VERSION 5.8 ;
BUSBITCHARS "[]" ;
DIVIDERCHAR "/" ;

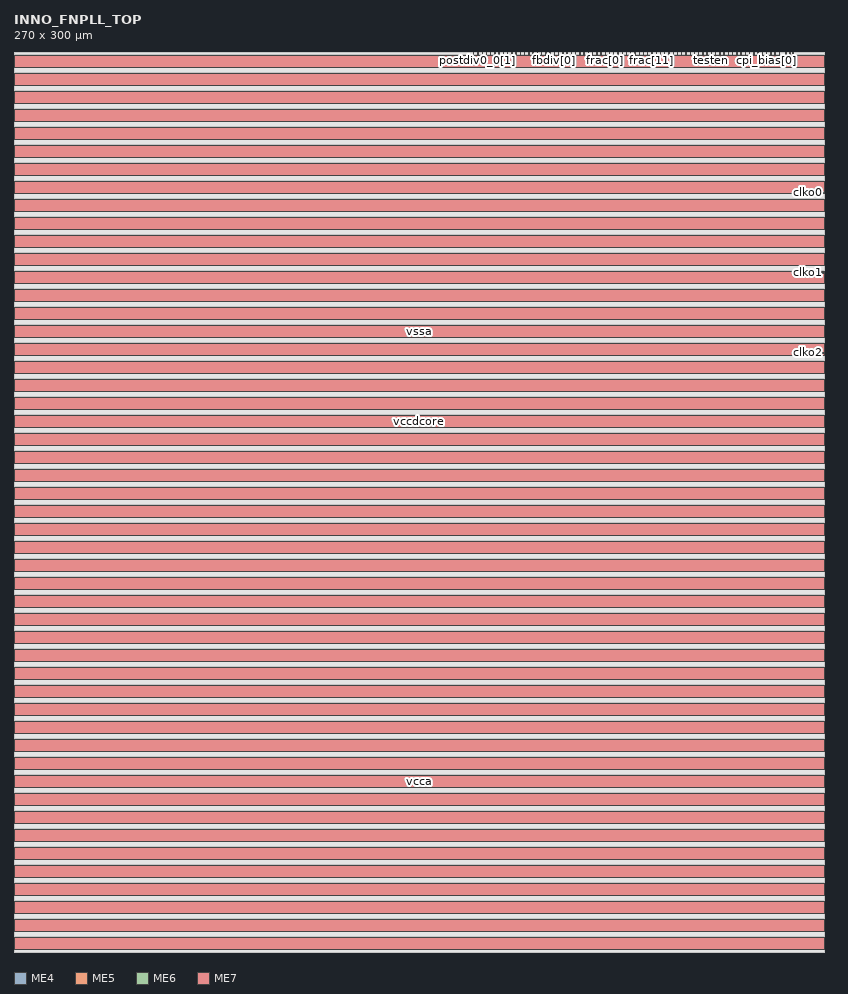
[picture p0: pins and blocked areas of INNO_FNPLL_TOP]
MACRO INNO_FNPLL_TOP
  CLASS BLOCK ;
  ORIGIN 0 0 ;
  FOREIGN INNO_FNPLL_TOP 0 0 ;
  SIZE 270 BY 300 ;
  SYMMETRY X Y ;
  PIN cpi_bias[0]
    DIRECTION INPUT ;
    USE SIGNAL ;
    PORT
      LAYER ME4 ;
        RECT 250.806 299 250.936 300 ;
    END
  END cpi_bias[0]
  PIN cpi_bias[1]
    DIRECTION INPUT ;
    USE SIGNAL ;
    PORT
      LAYER ME4 ;
        RECT 249.391 299 249.521 300 ;
    END
  END cpi_bias[1]
  PIN cpi_bias[2]
    DIRECTION INPUT ;
    USE SIGNAL ;
    PORT
      LAYER ME4 ;
        RECT 247.976 299 248.106 300 ;
    END
  END cpi_bias[2]
  PIN cpp_bias[0]
    DIRECTION INPUT ;
    USE SIGNAL ;
    PORT
      LAYER ME4 ;
        RECT 252.221 299 252.351 300 ;
    END
  END cpp_bias[0]
  PIN cpp_bias[1]
    DIRECTION INPUT ;
    USE SIGNAL ;
    PORT
      LAYER ME4 ;
        RECT 253.636 299 253.766 300 ;
    END
  END cpp_bias[1]
  PIN cpp_bias[2]
    DIRECTION INPUT ;
    USE SIGNAL ;
    PORT
      LAYER ME4 ;
        RECT 255.051 299 255.181 300 ;
    END
  END cpp_bias[2]
  PIN dacpd
    DIRECTION INPUT ;
    USE SIGNAL ;
    PORT
      LAYER ME4 ;
        RECT 233.826 299 233.956 300 ;
    END
  END dacpd
  PIN dsmpd
    DIRECTION INPUT ;
    USE SIGNAL ;
    PORT
      LAYER ME4 ;
        RECT 235.241 299 235.371 300 ;
    END
  END dsmpd
  PIN fbdiv[0]
    DIRECTION INPUT ;
    USE SIGNAL ;
    PORT
      LAYER ME4 ;
        RECT 180.056 299 180.186 300 ;
    END
  END fbdiv[0]
  PIN fbdiv[10]
    DIRECTION INPUT ;
    USE SIGNAL ;
    PORT
      LAYER ME4 ;
        RECT 194.206 299 194.336 300 ;
    END
  END fbdiv[10]
  PIN fbdiv[11]
    DIRECTION INPUT ;
    USE SIGNAL ;
    PORT
      LAYER ME4 ;
        RECT 195.621 299 195.751 300 ;
    END
  END fbdiv[11]
  PIN fbdiv[1]
    DIRECTION INPUT ;
    USE SIGNAL ;
    PORT
      LAYER ME4 ;
        RECT 181.471 299 181.601 300 ;
    END
  END fbdiv[1]
  PIN fbdiv[2]
    DIRECTION INPUT ;
    USE SIGNAL ;
    PORT
      LAYER ME4 ;
        RECT 182.886 299 183.016 300 ;
    END
  END fbdiv[2]
  PIN fbdiv[3]
    DIRECTION INPUT ;
    USE SIGNAL ;
    PORT
      LAYER ME4 ;
        RECT 184.301 299 184.431 300 ;
    END
  END fbdiv[3]
  PIN fbdiv[4]
    DIRECTION INPUT ;
    USE SIGNAL ;
    PORT
      LAYER ME4 ;
        RECT 185.716 299 185.846 300 ;
    END
  END fbdiv[4]
  PIN fbdiv[5]
    DIRECTION INPUT ;
    USE SIGNAL ;
    PORT
      LAYER ME4 ;
        RECT 187.131 299 187.261 300 ;
    END
  END fbdiv[5]
  PIN fbdiv[6]
    DIRECTION INPUT ;
    USE SIGNAL ;
    PORT
      LAYER ME4 ;
        RECT 188.546 299 188.676 300 ;
    END
  END fbdiv[6]
  PIN fbdiv[7]
    DIRECTION INPUT ;
    USE SIGNAL ;
    PORT
      LAYER ME4 ;
        RECT 189.961 299 190.091 300 ;
    END
  END fbdiv[7]
  PIN fbdiv[8]
    DIRECTION INPUT ;
    USE SIGNAL ;
    PORT
      LAYER ME4 ;
        RECT 191.376 299 191.506 300 ;
    END
  END fbdiv[8]
  PIN fbdiv[9]
    DIRECTION INPUT ;
    USE SIGNAL ;
    PORT
      LAYER ME4 ;
        RECT 192.791 299 192.921 300 ;
    END
  END fbdiv[9]
  PIN frac[0]
    DIRECTION INPUT ;
    USE SIGNAL ;
    PORT
      LAYER ME4 ;
        RECT 197.036 299 197.166 300 ;
    END
  END frac[0]
  PIN frac[10]
    DIRECTION INPUT ;
    USE SIGNAL ;
    PORT
      LAYER ME4 ;
        RECT 211.186 299 211.316 300 ;
    END
  END frac[10]
  PIN frac[11]
    DIRECTION INPUT ;
    USE SIGNAL ;
    PORT
      LAYER ME4 ;
        RECT 212.601 299 212.731 300 ;
    END
  END frac[11]
  PIN frac[12]
    DIRECTION INPUT ;
    USE SIGNAL ;
    PORT
      LAYER ME4 ;
        RECT 214.016 299 214.146 300 ;
    END
  END frac[12]
  PIN frac[13]
    DIRECTION INPUT ;
    USE SIGNAL ;
    PORT
      LAYER ME4 ;
        RECT 215.431 299 215.561 300 ;
    END
  END frac[13]
  PIN frac[14]
    DIRECTION INPUT ;
    USE SIGNAL ;
    PORT
      LAYER ME4 ;
        RECT 216.846 299 216.976 300 ;
    END
  END frac[14]
  PIN frac[15]
    DIRECTION INPUT ;
    USE SIGNAL ;
    PORT
      LAYER ME4 ;
        RECT 218.261 299 218.391 300 ;
    END
  END frac[15]
  PIN frac[16]
    DIRECTION INPUT ;
    USE SIGNAL ;
    PORT
      LAYER ME4 ;
        RECT 219.676 299 219.806 300 ;
    END
  END frac[16]
  PIN frac[17]
    DIRECTION INPUT ;
    USE SIGNAL ;
    PORT
      LAYER ME4 ;
        RECT 221.091 299 221.221 300 ;
    END
  END frac[17]
  PIN frac[18]
    DIRECTION INPUT ;
    USE SIGNAL ;
    PORT
      LAYER ME4 ;
        RECT 222.506 299 222.636 300 ;
    END
  END frac[18]
  PIN frac[19]
    DIRECTION INPUT ;
    USE SIGNAL ;
    PORT
      LAYER ME4 ;
        RECT 223.921 299 224.051 300 ;
    END
  END frac[19]
  PIN frac[1]
    DIRECTION INPUT ;
    USE SIGNAL ;
    PORT
      LAYER ME4 ;
        RECT 198.451 299 198.581 300 ;
    END
  END frac[1]
  PIN frac[20]
    DIRECTION INPUT ;
    USE SIGNAL ;
    PORT
      LAYER ME4 ;
        RECT 225.336 299 225.466 300 ;
    END
  END frac[20]
  PIN frac[21]
    DIRECTION INPUT ;
    USE SIGNAL ;
    PORT
      LAYER ME4 ;
        RECT 226.751 299 226.881 300 ;
    END
  END frac[21]
  PIN frac[22]
    DIRECTION INPUT ;
    USE SIGNAL ;
    PORT
      LAYER ME4 ;
        RECT 228.166 299 228.296 300 ;
    END
  END frac[22]
  PIN frac[23]
    DIRECTION INPUT ;
    USE SIGNAL ;
    PORT
      LAYER ME4 ;
        RECT 229.581 299 229.711 300 ;
    END
  END frac[23]
  PIN frac[2]
    DIRECTION INPUT ;
    USE SIGNAL ;
    PORT
      LAYER ME4 ;
        RECT 199.866 299 199.996 300 ;
    END
  END frac[2]
  PIN frac[3]
    DIRECTION INPUT ;
    USE SIGNAL ;
    PORT
      LAYER ME4 ;
        RECT 201.281 299 201.411 300 ;
    END
  END frac[3]
  PIN frac[4]
    DIRECTION INPUT ;
    USE SIGNAL ;
    PORT
      LAYER ME4 ;
        RECT 202.696 299 202.826 300 ;
    END
  END frac[4]
  PIN frac[5]
    DIRECTION INPUT ;
    USE SIGNAL ;
    PORT
      LAYER ME4 ;
        RECT 204.111 299 204.241 300 ;
    END
  END frac[5]
  PIN frac[6]
    DIRECTION INPUT ;
    USE SIGNAL ;
    PORT
      LAYER ME4 ;
        RECT 205.526 299 205.656 300 ;
    END
  END frac[6]
  PIN frac[7]
    DIRECTION INPUT ;
    USE SIGNAL ;
    PORT
      LAYER ME4 ;
        RECT 206.941 299 207.071 300 ;
    END
  END frac[7]
  PIN frac[8]
    DIRECTION INPUT ;
    USE SIGNAL ;
    PORT
      LAYER ME4 ;
        RECT 208.356 299 208.486 300 ;
    END
  END frac[8]
  PIN frac[9]
    DIRECTION INPUT ;
    USE SIGNAL ;
    PORT
      LAYER ME4 ;
        RECT 209.771 299 209.901 300 ;
    END
  END frac[9]
  PIN gvco_bias[0]
    DIRECTION INPUT ;
    USE SIGNAL ;
    PORT
      LAYER ME4 ;
        RECT 246.561 299 246.691 300 ;
    END
  END gvco_bias[0]
  PIN gvco_bias[1]
    DIRECTION INPUT ;
    USE SIGNAL ;
    PORT
      LAYER ME4 ;
        RECT 245.146 299 245.276 300 ;
    END
  END gvco_bias[1]
  PIN pd
    DIRECTION INPUT ;
    USE SIGNAL ;
    PORT
      LAYER ME4 ;
        RECT 243.731 299 243.861 300 ;
    END
  END pd
  PIN postdiv0_0[0]
    DIRECTION INPUT ;
    USE SIGNAL ;
    PORT
      LAYER ME4 ;
        RECT 165.906 299 166.036 300 ;
    END
  END postdiv0_0[0]
  PIN postdiv0_0[1]
    DIRECTION INPUT ;
    USE SIGNAL ;
    PORT
      LAYER ME4 ;
        RECT 154.586 299 154.716 300 ;
    END
  END postdiv0_0[1]
  PIN postdiv0_0[2]
    DIRECTION INPUT ;
    USE SIGNAL ;
    PORT
      LAYER ME4 ;
        RECT 161.661 299 161.791 300 ;
    END
  END postdiv0_0[2]
  PIN postdiv0_1[0]
    DIRECTION INPUT ;
    USE SIGNAL ;
    PORT
      LAYER ME4 ;
        RECT 164.491 299 164.621 300 ;
    END
  END postdiv0_1[0]
  PIN postdiv0_1[1]
    DIRECTION INPUT ;
    USE SIGNAL ;
    PORT
      LAYER ME4 ;
        RECT 156.001 299 156.131 300 ;
    END
  END postdiv0_1[1]
  PIN postdiv0_1[2]
    DIRECTION INPUT ;
    USE SIGNAL ;
    PORT
      LAYER ME4 ;
        RECT 160.246 299 160.376 300 ;
    END
  END postdiv0_1[2]
  PIN postdiv0_2[0]
    DIRECTION INPUT ;
    USE SIGNAL ;
    PORT
      LAYER ME4 ;
        RECT 163.076 299 163.206 300 ;
    END
  END postdiv0_2[0]
  PIN postdiv0_2[1]
    DIRECTION INPUT ;
    USE SIGNAL ;
    PORT
      LAYER ME4 ;
        RECT 157.416 299 157.546 300 ;
    END
  END postdiv0_2[1]
  PIN postdiv0_2[2]
    DIRECTION INPUT ;
    USE SIGNAL ;
    PORT
      LAYER ME4 ;
        RECT 158.831 299 158.961 300 ;
    END
  END postdiv0_2[2]
  PIN postdiv1_0[0]
    DIRECTION INPUT ;
    USE SIGNAL ;
    PORT
      LAYER ME4 ;
        RECT 175.811 299 175.941 300 ;
    END
  END postdiv1_0[0]
  PIN postdiv1_0[1]
    DIRECTION INPUT ;
    USE SIGNAL ;
    PORT
      LAYER ME4 ;
        RECT 168.736 299 168.866 300 ;
    END
  END postdiv1_0[1]
  PIN postdiv1_0[2]
    DIRECTION INPUT ;
    USE SIGNAL ;
    PORT
      LAYER ME4 ;
        RECT 171.566 299 171.696 300 ;
    END
  END postdiv1_0[2]
  PIN postdiv1_1[0]
    DIRECTION INPUT ;
    USE SIGNAL ;
    PORT
      LAYER ME4 ;
        RECT 177.226 299 177.356 300 ;
    END
  END postdiv1_1[0]
  PIN postdiv1_1[1]
    DIRECTION INPUT ;
    USE SIGNAL ;
    PORT
      LAYER ME4 ;
        RECT 170.151 299 170.281 300 ;
    END
  END postdiv1_1[1]
  PIN postdiv1_1[2]
    DIRECTION INPUT ;
    USE SIGNAL ;
    PORT
      LAYER ME4 ;
        RECT 172.981 299 173.111 300 ;
    END
  END postdiv1_1[2]
  PIN postdiv1_2[0]
    DIRECTION INPUT ;
    USE SIGNAL ;
    PORT
      LAYER ME4 ;
        RECT 178.641 299 178.771 300 ;
    END
  END postdiv1_2[0]
  PIN postdiv1_2[1]
    DIRECTION INPUT ;
    USE SIGNAL ;
    PORT
      LAYER ME4 ;
        RECT 167.321 299 167.451 300 ;
    END
  END postdiv1_2[1]
  PIN postdiv1_2[2]
    DIRECTION INPUT ;
    USE SIGNAL ;
    PORT
      LAYER ME4 ;
        RECT 174.396 299 174.526 300 ;
    END
  END postdiv1_2[2]
  PIN prediv[0]
    DIRECTION INPUT ;
    USE SIGNAL ;
    PORT
      LAYER ME4 ;
        RECT 240.901 299 241.031 300 ;
    END
  END prediv[0]
  PIN prediv[1]
    DIRECTION INPUT ;
    USE SIGNAL ;
    PORT
      LAYER ME4 ;
        RECT 238.071 299 238.201 300 ;
    END
  END prediv[1]
  PIN prediv[2]
    DIRECTION INPUT ;
    USE SIGNAL ;
    PORT
      LAYER ME4 ;
        RECT 236.656 299 236.786 300 ;
    END
  END prediv[2]
  PIN prediv[3]
    DIRECTION INPUT ;
    USE SIGNAL ;
    PORT
      LAYER ME4 ;
        RECT 239.486 299 239.616 300 ;
    END
  END prediv[3]
  PIN prediv[4]
    DIRECTION INPUT ;
    USE SIGNAL ;
    PORT
      LAYER ME4 ;
        RECT 242.316 299 242.446 300 ;
    END
  END prediv[4]
  PIN testen
    DIRECTION INPUT ;
    USE SIGNAL ;
    PORT
      LAYER ME4 ;
        RECT 232.411 299 232.541 300 ;
    END
  END testen
  PIN testsel[0]
    DIRECTION INPUT ;
    USE SIGNAL ;
    PORT
      LAYER ME4 ;
        RECT 153.171 299 153.301 300 ;
    END
  END testsel[0]
  PIN testsel[1]
    DIRECTION INPUT ;
    USE SIGNAL ;
    PORT
      LAYER ME4 ;
        RECT 230.996 299 231.126 300 ;
    END
  END testsel[1]
  PIN clko0
    DIRECTION OUTPUT ;
    USE SIGNAL ;
    PORT
      LAYER ME5 ;
        RECT 269 252.975 270 253.275 ;
    END
  END clko0
  PIN clko1
    DIRECTION OUTPUT ;
    USE SIGNAL ;
    PORT
      LAYER ME5 ;
        RECT 269 226.275 270 226.575 ;
    END
  END clko1
  PIN clko2
    DIRECTION OUTPUT ;
    USE SIGNAL ;
    PORT
      LAYER ME5 ;
        RECT 269 199.575 270 199.875 ;
    END
  END clko2
  PIN lock
    DIRECTION OUTPUT ;
    USE SIGNAL ;
    PORT
      LAYER ME6 ;
        RECT 259.606 299 259.806 300 ;
    END
  END lock
  PIN refclk
    DIRECTION INPUT ;
    USE SIGNAL ;
    PORT
      LAYER ME6 ;
        RECT 257.166 299 257.466 300 ;
    END
  END refclk
  PIN testout
    DIRECTION OUTPUT ;
    USE SIGNAL ;
    PORT
      LAYER ME6 ;
        RECT 258.536 299 258.736 300 ;
    END
  END testout
  PIN vcca
    DIRECTION INOUT ;
    USE POWER ;
    PORT
      LAYER ME7 ;
        RECT 0 55 270 59 ;
    END
    PORT
      LAYER ME7 ;
        RECT 0 103 270 107 ;
    END
    PORT
      LAYER ME7 ;
        RECT 0 115 270 119 ;
    END
    PORT
      LAYER ME7 ;
        RECT 0 91 270 95 ;
    END
    PORT
      LAYER ME7 ;
        RECT 0 127 270 131 ;
    END
    PORT
      LAYER ME7 ;
        RECT 0 79 270 83 ;
    END
    PORT
      LAYER ME7 ;
        RECT 0 139 270 143 ;
    END
    PORT
      LAYER ME7 ;
        RECT 0 67 270 71 ;
    END
    PORT
      LAYER ME7 ;
        RECT 0 43 270 47 ;
    END
    PORT
      LAYER ME7 ;
        RECT 0 31 270 35 ;
    END
    PORT
      LAYER ME7 ;
        RECT 0 19 270 23 ;
    END
    PORT
      LAYER ME7 ;
        RECT 0 7 270 11 ;
    END
  END vcca
  PIN vccdcore
    DIRECTION INOUT ;
    USE POWER ;
    PORT
      LAYER ME7 ;
        RECT 0 175 270 179 ;
    END
    PORT
      LAYER ME7 ;
        RECT 0 151 270 155 ;
    END
    PORT
      LAYER ME7 ;
        RECT 0 163 270 167 ;
    END
    PORT
      LAYER ME7 ;
        RECT 0 187 270 191 ;
    END
    PORT
      LAYER ME7 ;
        RECT 0 199 270 203 ;
    END
    PORT
      LAYER ME7 ;
        RECT 0 211 270 215 ;
    END
  END vccdcore
  PIN vccdpost
    DIRECTION INOUT ;
    USE SIGNAL ;
    PORT
      LAYER ME7 ;
        RECT 0 295 270 299 ;
    END
    PORT
      LAYER ME7 ;
        RECT 0 283 270 287 ;
    END
    PORT
      LAYER ME7 ;
        RECT 0 271 270 275 ;
    END
    PORT
      LAYER ME7 ;
        RECT 0 259 270 263 ;
    END
    PORT
      LAYER ME7 ;
        RECT 0 247 270 251 ;
    END
    PORT
      LAYER ME7 ;
        RECT 0 235 270 239 ;
    END
    PORT
      LAYER ME7 ;
        RECT 0 223 270 227 ;
    END
  END vccdpost
  PIN vssa
    DIRECTION INOUT ;
    USE GROUND ;
    PORT
      LAYER ME7 ;
        RECT 0 205 270 209 ;
    END
    PORT
      LAYER ME7 ;
        RECT 0 289 270 293 ;
    END
    PORT
      LAYER ME7 ;
        RECT 0 277 270 281 ;
    END
    PORT
      LAYER ME7 ;
        RECT 0 265 270 269 ;
    END
    PORT
      LAYER ME7 ;
        RECT 0 253 270 257 ;
    END
    PORT
      LAYER ME7 ;
        RECT 0 241 270 245 ;
    END
    PORT
      LAYER ME7 ;
        RECT 0 229 270 233 ;
    END
    PORT
      LAYER ME7 ;
        RECT 0 217 270 221 ;
    END
    PORT
      LAYER ME7 ;
        RECT 0 13 270 17 ;
    END
    PORT
      LAYER ME7 ;
        RECT 0 109 270 113 ;
    END
    PORT
      LAYER ME7 ;
        RECT 0 25 270 29 ;
    END
    PORT
      LAYER ME7 ;
        RECT 0 193 270 197 ;
    END
    PORT
      LAYER ME7 ;
        RECT 0 37 270 41 ;
    END
    PORT
      LAYER ME7 ;
        RECT 0 181 270 185 ;
    END
    PORT
      LAYER ME7 ;
        RECT 0 49 270 53 ;
    END
    PORT
      LAYER ME7 ;
        RECT 0 169 270 173 ;
    END
    PORT
      LAYER ME7 ;
        RECT 0 61 270 65 ;
    END
    PORT
      LAYER ME7 ;
        RECT 0 157 270 161 ;
    END
    PORT
      LAYER ME7 ;
        RECT 0 1 270 5 ;
    END
    PORT
      LAYER ME7 ;
        RECT 0 145 270 149 ;
    END
    PORT
      LAYER ME7 ;
        RECT 0 73 270 77 ;
    END
    PORT
      LAYER ME7 ;
        RECT 0 133 270 137 ;
    END
    PORT
      LAYER ME7 ;
        RECT 0 85 270 89 ;
    END
    PORT
      LAYER ME7 ;
        RECT 0 121 270 125 ;
    END
    PORT
      LAYER ME7 ;
        RECT 0 97 270 101 ;
    END
  END vssa
  OBS
    LAYER ME1 SPACING 0.07 ;
      RECT 0 0 270 300 ;
    LAYER ME2 SPACING 0.07 ;
      RECT 0 0 270 300 ;
    LAYER ME3 SPACING 0.07 ;
      RECT 0 0 270 300 ;
    LAYER ME4 SPACING 0.07 ;
      POLYGON 270 300 255.251 300 255.251 298.93 254.981 298.93 254.981 300 253.836 300 253.836 298.93 253.566 298.93 253.566 300 252.421 300 252.421 298.93 252.151 298.93 252.151 300 251.006 300 251.006 298.93 250.736 298.93 250.736 300 249.591 300 249.591 298.93 249.321 298.93 249.321 300 248.176 300 248.176 298.93 247.906 298.93 247.906 300 246.761 300 246.761 298.93 246.491 298.93 246.491 300 245.346 300 245.346 298.93 245.076 298.93 245.076 300 243.931 300 243.931 298.93 243.661 298.93 243.661 300 242.516 300 242.516 298.93 242.246 298.93 242.246 300 241.101 300 241.101 298.93 240.831 298.93 240.831 300 239.686 300 239.686 298.93 239.416 298.93 239.416 300 238.271 300 238.271 298.93 238.001 298.93 238.001 300 236.856 300 236.856 298.93 236.586 298.93 236.586 300 235.441 300 235.441 298.93 235.171 298.93 235.171 300 234.026 300 234.026 298.93 233.756 298.93 233.756 300 232.611 300 232.611 298.93 232.341 298.93 232.341 300 231.196 300 231.196 298.93 230.926 298.93 230.926 300 229.781 300 229.781 298.93 229.511 298.93 229.511 300 228.366 300 228.366 298.93 228.096 298.93 228.096 300 226.951 300 226.951 298.93 226.681 298.93 226.681 300 225.536 300 225.536 298.93 225.266 298.93 225.266 300 224.121 300 224.121 298.93 223.851 298.93 223.851 300 222.706 300 222.706 298.93 222.436 298.93 222.436 300 221.291 300 221.291 298.93 221.021 298.93 221.021 300 219.876 300 219.876 298.93 219.606 298.93 219.606 300 218.461 300 218.461 298.93 218.191 298.93 218.191 300 217.046 300 217.046 298.93 216.776 298.93 216.776 300 215.631 300 215.631 298.93 215.361 298.93 215.361 300 214.216 300 214.216 298.93 213.946 298.93 213.946 300 212.801 300 212.801 298.93 212.531 298.93 212.531 300 211.386 300 211.386 298.93 211.116 298.93 211.116 300 209.971 300 209.971 298.93 209.701 298.93 209.701 300 208.556 300 208.556 298.93 208.286 298.93 208.286 300 207.141 300 207.141 298.93 206.871 298.93 206.871 300 205.726 300 205.726 298.93 205.456 298.93 205.456 300 204.311 300 204.311 298.93 204.041 298.93 204.041 300 202.896 300 202.896 298.93 202.626 298.93 202.626 300 201.481 300 201.481 298.93 201.211 298.93 201.211 300 200.066 300 200.066 298.93 199.796 298.93 199.796 300 198.651 300 198.651 298.93 198.381 298.93 198.381 300 197.236 300 197.236 298.93 196.966 298.93 196.966 300 195.821 300 195.821 298.93 195.551 298.93 195.551 300 194.406 300 194.406 298.93 194.136 298.93 194.136 300 192.991 300 192.991 298.93 192.721 298.93 192.721 300 191.576 300 191.576 298.93 191.306 298.93 191.306 300 190.161 300 190.161 298.93 189.891 298.93 189.891 300 188.746 300 188.746 298.93 188.476 298.93 188.476 300 187.331 300 187.331 298.93 187.061 298.93 187.061 300 185.916 300 185.916 298.93 185.646 298.93 185.646 300 184.501 300 184.501 298.93 184.231 298.93 184.231 300 183.086 300 183.086 298.93 182.816 298.93 182.816 300 181.671 300 181.671 298.93 181.401 298.93 181.401 300 180.256 300 180.256 298.93 179.986 298.93 179.986 300 178.841 300 178.841 298.93 178.571 298.93 178.571 300 177.426 300 177.426 298.93 177.156 298.93 177.156 300 176.011 300 176.011 298.93 175.741 298.93 175.741 300 174.596 300 174.596 298.93 174.326 298.93 174.326 300 173.181 300 173.181 298.93 172.911 298.93 172.911 300 171.766 300 171.766 298.93 171.496 298.93 171.496 300 170.351 300 170.351 298.93 170.081 298.93 170.081 300 168.936 300 168.936 298.93 168.666 298.93 168.666 300 167.521 300 167.521 298.93 167.251 298.93 167.251 300 166.106 300 166.106 298.93 165.836 298.93 165.836 300 164.691 300 164.691 298.93 164.421 298.93 164.421 300 163.276 300 163.276 298.93 163.006 298.93 163.006 300 161.861 300 161.861 298.93 161.591 298.93 161.591 300 160.446 300 160.446 298.93 160.176 298.93 160.176 300 159.031 300 159.031 298.93 158.761 298.93 158.761 300 157.616 300 157.616 298.93 157.346 298.93 157.346 300 156.201 300 156.201 298.93 155.931 298.93 155.931 300 154.786 300 154.786 298.93 154.516 298.93 154.516 300 153.371 300 153.371 298.93 153.101 298.93 153.101 300 0 300 0 0 270 0 ;
    LAYER ME5 ;
      RECT 269 198.905 270 198.975 ;
      RECT 269 200.475 270 200.545 ;
      RECT 269 225.605 270 225.675 ;
      RECT 269 227.175 270 227.245 ;
      RECT 269 252.305 270 252.375 ;
      RECT 269 253.875 270 253.945 ;
    LAYER ME5 SPACING 0.07 ;
      POLYGON 270 199.505 268.93 199.505 268.93 199.945 270 199.945 270 226.205 268.93 226.205 268.93 226.645 270 226.645 270 252.905 268.93 252.905 268.93 253.345 270 253.345 270 300 0 300 0 0 270 0 ;
    LAYER ME6 ;
      RECT 260.206 299 260.276 300 ;
      RECT 259.136 299 259.206 300 ;
      RECT 258.066 299 258.136 300 ;
      RECT 256.496 299 256.566 300 ;
    LAYER ME6 SPACING 0.07 ;
      POLYGON 270 300 259.876 300 259.876 298.93 259.536 298.93 259.536 300 258.806 300 258.806 298.93 258.466 298.93 258.466 300 257.536 300 257.536 298.93 257.096 298.93 257.096 300 0 300 0 0 270 0 ;
    LAYER ME7 SPACING 0.14 ;
      RECT 0 0 270 0.86 ;
      RECT 0 5.14 270 6.86 ;
      RECT 0 11.14 270 12.86 ;
      RECT 0 17.14 270 18.86 ;
      RECT 0 23.14 270 24.86 ;
      RECT 0 29.14 270 30.86 ;
      RECT 0 35.14 270 36.86 ;
      RECT 0 41.14 270 42.86 ;
      RECT 0 47.14 270 48.86 ;
      RECT 0 53.14 270 54.86 ;
      RECT 0 59.14 270 60.86 ;
      RECT 0 65.14 270 66.86 ;
      RECT 0 71.14 270 72.86 ;
      RECT 0 77.14 270 78.86 ;
      RECT 0 83.14 270 84.86 ;
      RECT 0 89.14 270 90.86 ;
      RECT 0 95.14 270 96.86 ;
      RECT 0 101.14 270 102.86 ;
      RECT 0 107.14 270 108.86 ;
      RECT 0 113.14 270 114.86 ;
      RECT 0 119.14 270 120.86 ;
      RECT 0 125.14 270 126.86 ;
      RECT 0 131.14 270 132.86 ;
      RECT 0 137.14 270 138.86 ;
      RECT 0 143.14 270 144.86 ;
      RECT 0 149.14 270 150.86 ;
      RECT 0 155.14 270 156.86 ;
      RECT 0 161.14 270 162.86 ;
      RECT 0 167.14 270 168.86 ;
      RECT 0 173.14 270 174.86 ;
      RECT 0 179.14 270 180.86 ;
      RECT 0 185.14 270 186.86 ;
      RECT 0 191.14 270 192.86 ;
      RECT 0 197.14 270 198.86 ;
      RECT 0 203.14 270 204.86 ;
      RECT 0 209.14 270 210.86 ;
      RECT 0 215.14 270 216.86 ;
      RECT 0 221.14 270 222.86 ;
      RECT 0 227.14 270 228.86 ;
      RECT 0 233.14 270 234.86 ;
      RECT 0 239.14 270 240.86 ;
      RECT 0 245.14 270 246.86 ;
      RECT 0 251.14 270 252.86 ;
      RECT 0 257.14 270 258.86 ;
      RECT 0 263.14 270 264.86 ;
      RECT 0 269.14 270 270.86 ;
      RECT 0 275.14 270 276.86 ;
      RECT 0 281.14 270 282.86 ;
      RECT 0 287.14 270 288.86 ;
      RECT 0 293.14 270 294.86 ;
      RECT 0 299.14 270 300 ;
  END
END INNO_FNPLL_TOP

END LIBRARY
